VERSION 5.7 ;
  NOWIREEXTENSIONATPIN ON ;
  DIVIDERCHAR "/" ;
  BUSBITCHARS "[]" ;
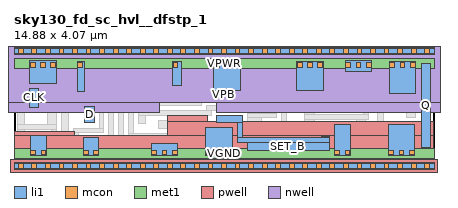
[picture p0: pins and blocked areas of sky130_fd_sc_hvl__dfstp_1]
MACRO sky130_fd_sc_hvl__dfstp_1
  CLASS BLOCK ;
  FOREIGN sky130_fd_sc_hvl__dfstp_1 ;
  ORIGIN 0.000 0.000 ;
  SIZE 14.880 BY 4.070 ;
  PIN CLK
    ANTENNAGATEAREA 0.585000 ;
    PORT
      LAYER li1 ;
        RECT 0.545 2.075 0.875 2.745 ;
    END
  END CLK
  PIN D
    ANTENNAGATEAREA 0.420000 ;
    PORT
      LAYER li1 ;
        RECT 2.505 1.525 2.835 2.095 ;
    END
  END D
  PIN SET_B
    ANTENNAGATEAREA 0.840000 ;
    PORT
      LAYER li1 ;
        RECT 7.165 1.555 8.100 1.795 ;
        RECT 7.930 1.010 8.100 1.555 ;
        RECT 10.885 1.010 11.160 1.040 ;
        RECT 7.930 0.840 11.160 1.010 ;
        RECT 8.285 0.555 11.160 0.840 ;
    END
  END SET_B
  PIN VGND
    USE GROUND ;
    PORT
      LAYER li1 ;
        RECT 0.570 0.365 1.160 1.115 ;
        RECT 2.470 0.365 3.005 0.995 ;
        RECT 4.855 0.365 5.805 0.785 ;
        RECT 6.800 0.365 7.750 1.375 ;
        RECT 11.340 0.365 11.930 1.475 ;
        RECT 13.255 0.365 14.205 1.475 ;
      LAYER mcon ;
        RECT 0.600 0.395 0.770 0.565 ;
        RECT 0.960 0.395 1.130 0.565 ;
        RECT 2.470 0.395 2.640 0.565 ;
        RECT 2.830 0.395 3.000 0.565 ;
        RECT 4.885 0.395 5.055 0.565 ;
        RECT 5.245 0.395 5.415 0.565 ;
        RECT 5.605 0.395 5.775 0.565 ;
        RECT 6.830 0.395 7.000 0.565 ;
        RECT 7.190 0.395 7.360 0.565 ;
        RECT 7.550 0.395 7.720 0.565 ;
        RECT 11.370 0.395 11.540 0.565 ;
        RECT 11.730 0.395 11.900 0.565 ;
        RECT 13.285 0.395 13.455 0.565 ;
        RECT 13.645 0.395 13.815 0.565 ;
        RECT 14.005 0.395 14.175 0.565 ;
      LAYER met1 ;
        RECT 0.000 0.255 14.880 0.625 ;
    END
  END VGND
  PIN VNB
    ANTENNADIFFAREA 2.529600 ;
    PORT
      LAYER pwell ;
        RECT 5.445 1.565 6.870 1.805 ;
        RECT 0.020 1.085 2.130 1.205 ;
        RECT 5.445 1.085 14.860 1.565 ;
        RECT 0.020 0.215 14.860 1.085 ;
        RECT -0.130 -0.215 15.010 0.215 ;
      LAYER li1 ;
        RECT 0.000 -0.085 14.880 0.085 ;
      LAYER mcon ;
        RECT 0.155 -0.085 0.325 0.085 ;
        RECT 0.635 -0.085 0.805 0.085 ;
        RECT 1.115 -0.085 1.285 0.085 ;
        RECT 1.595 -0.085 1.765 0.085 ;
        RECT 2.075 -0.085 2.245 0.085 ;
        RECT 2.555 -0.085 2.725 0.085 ;
        RECT 3.035 -0.085 3.205 0.085 ;
        RECT 3.515 -0.085 3.685 0.085 ;
        RECT 3.995 -0.085 4.165 0.085 ;
        RECT 4.475 -0.085 4.645 0.085 ;
        RECT 4.955 -0.085 5.125 0.085 ;
        RECT 5.435 -0.085 5.605 0.085 ;
        RECT 5.915 -0.085 6.085 0.085 ;
        RECT 6.395 -0.085 6.565 0.085 ;
        RECT 6.875 -0.085 7.045 0.085 ;
        RECT 7.355 -0.085 7.525 0.085 ;
        RECT 7.835 -0.085 8.005 0.085 ;
        RECT 8.315 -0.085 8.485 0.085 ;
        RECT 8.795 -0.085 8.965 0.085 ;
        RECT 9.275 -0.085 9.445 0.085 ;
        RECT 9.755 -0.085 9.925 0.085 ;
        RECT 10.235 -0.085 10.405 0.085 ;
        RECT 10.715 -0.085 10.885 0.085 ;
        RECT 11.195 -0.085 11.365 0.085 ;
        RECT 11.675 -0.085 11.845 0.085 ;
        RECT 12.155 -0.085 12.325 0.085 ;
        RECT 12.635 -0.085 12.805 0.085 ;
        RECT 13.115 -0.085 13.285 0.085 ;
        RECT 13.595 -0.085 13.765 0.085 ;
        RECT 14.075 -0.085 14.245 0.085 ;
        RECT 14.555 -0.085 14.725 0.085 ;
      LAYER met1 ;
        RECT 0.000 -0.115 14.880 0.115 ;
    END
  END VNB
  PIN VPB
    ANTENNADIFFAREA 2.529600 ;
    PORT
      LAYER nwell ;
        RECT -0.330 2.245 15.210 4.485 ;
        RECT -0.330 1.885 5.145 2.245 ;
        RECT 7.170 1.885 15.210 2.245 ;
      LAYER li1 ;
        RECT 0.000 3.985 14.880 4.155 ;
      LAYER mcon ;
        RECT 0.155 3.985 0.325 4.155 ;
        RECT 0.635 3.985 0.805 4.155 ;
        RECT 1.115 3.985 1.285 4.155 ;
        RECT 1.595 3.985 1.765 4.155 ;
        RECT 2.075 3.985 2.245 4.155 ;
        RECT 2.555 3.985 2.725 4.155 ;
        RECT 3.035 3.985 3.205 4.155 ;
        RECT 3.515 3.985 3.685 4.155 ;
        RECT 3.995 3.985 4.165 4.155 ;
        RECT 4.475 3.985 4.645 4.155 ;
        RECT 4.955 3.985 5.125 4.155 ;
        RECT 5.435 3.985 5.605 4.155 ;
        RECT 5.915 3.985 6.085 4.155 ;
        RECT 6.395 3.985 6.565 4.155 ;
        RECT 6.875 3.985 7.045 4.155 ;
        RECT 7.355 3.985 7.525 4.155 ;
        RECT 7.835 3.985 8.005 4.155 ;
        RECT 8.315 3.985 8.485 4.155 ;
        RECT 8.795 3.985 8.965 4.155 ;
        RECT 9.275 3.985 9.445 4.155 ;
        RECT 9.755 3.985 9.925 4.155 ;
        RECT 10.235 3.985 10.405 4.155 ;
        RECT 10.715 3.985 10.885 4.155 ;
        RECT 11.195 3.985 11.365 4.155 ;
        RECT 11.675 3.985 11.845 4.155 ;
        RECT 12.155 3.985 12.325 4.155 ;
        RECT 12.635 3.985 12.805 4.155 ;
        RECT 13.115 3.985 13.285 4.155 ;
        RECT 13.595 3.985 13.765 4.155 ;
        RECT 14.075 3.985 14.245 4.155 ;
        RECT 14.555 3.985 14.725 4.155 ;
      LAYER met1 ;
        RECT 0.000 3.955 14.880 4.185 ;
    END
  END VPB
  PIN VPWR
    USE POWER ;
    PORT
      LAYER li1 ;
        RECT 0.545 2.925 1.495 3.755 ;
        RECT 2.235 2.625 2.485 3.705 ;
        RECT 5.605 2.855 5.935 3.705 ;
        RECT 7.075 2.675 8.025 3.705 ;
        RECT 10.010 2.665 10.960 3.705 ;
        RECT 11.730 3.355 12.680 3.735 ;
        RECT 13.295 2.575 14.240 3.705 ;
      LAYER mcon ;
        RECT 0.575 3.505 0.745 3.675 ;
        RECT 0.935 3.505 1.105 3.675 ;
        RECT 1.295 3.505 1.465 3.675 ;
        RECT 2.265 3.505 2.435 3.675 ;
        RECT 5.635 3.505 5.805 3.675 ;
        RECT 7.105 3.505 7.275 3.675 ;
        RECT 7.465 3.505 7.635 3.675 ;
        RECT 7.825 3.505 7.995 3.675 ;
        RECT 10.040 3.505 10.210 3.675 ;
        RECT 10.400 3.505 10.570 3.675 ;
        RECT 10.760 3.505 10.930 3.675 ;
        RECT 11.760 3.505 11.930 3.675 ;
        RECT 12.120 3.505 12.290 3.675 ;
        RECT 12.480 3.505 12.650 3.675 ;
        RECT 13.320 3.505 13.490 3.675 ;
        RECT 13.680 3.505 13.850 3.675 ;
        RECT 14.040 3.505 14.210 3.675 ;
      LAYER met1 ;
        RECT 0.000 3.445 14.880 3.815 ;
    END
  END VPWR
  PIN Q
    ANTENNADIFFAREA 0.478750 ;
    PORT
      LAYER li1 ;
        RECT 14.420 0.645 14.770 3.615 ;
    END
  END Q
  OBS
      LAYER li1 ;
        RECT 0.115 1.465 0.365 3.735 ;
        RECT 1.675 2.945 2.005 3.735 ;
        RECT 1.690 2.445 2.005 2.945 ;
        RECT 2.665 2.445 2.835 3.755 ;
        RECT 1.690 2.275 2.835 2.445 ;
        RECT 3.015 3.285 5.005 3.615 ;
        RECT 8.695 3.595 9.825 3.805 ;
        RECT 1.180 1.465 1.510 1.895 ;
        RECT 0.115 1.295 1.510 1.465 ;
        RECT 0.115 0.615 0.380 1.295 ;
        RECT 1.340 0.435 1.510 1.295 ;
        RECT 1.690 0.615 1.940 2.275 ;
        RECT 3.015 1.345 3.185 3.285 ;
        RECT 2.120 1.175 3.185 1.345 ;
        RECT 2.120 0.435 2.290 1.175 ;
        RECT 3.365 0.995 3.535 3.105 ;
        RECT 3.715 1.085 3.885 3.285 ;
        RECT 4.065 2.605 4.395 3.105 ;
        RECT 4.065 1.135 4.235 2.605 ;
        RECT 4.835 2.325 5.005 3.285 ;
        RECT 5.185 2.675 5.425 3.555 ;
        RECT 6.565 2.845 6.895 3.105 ;
        RECT 6.115 2.675 6.895 2.845 ;
        RECT 8.695 2.845 8.865 3.595 ;
        RECT 9.045 3.025 9.660 3.415 ;
        RECT 11.300 3.255 11.550 3.755 ;
        RECT 8.695 2.675 9.310 2.845 ;
        RECT 5.185 2.505 6.285 2.675 ;
        RECT 6.465 2.325 8.960 2.495 ;
        RECT 4.415 1.975 4.655 2.165 ;
        RECT 4.835 2.155 6.635 2.325 ;
        RECT 6.815 1.975 8.450 2.145 ;
        RECT 8.630 2.085 8.960 2.325 ;
        RECT 4.415 1.805 6.985 1.975 ;
        RECT 8.280 1.875 8.450 1.975 ;
        RECT 9.140 1.875 9.310 2.675 ;
        RECT 4.415 1.495 4.655 1.805 ;
        RECT 8.280 1.705 9.310 1.875 ;
        RECT 9.490 2.485 9.660 3.025 ;
        RECT 11.380 3.175 11.550 3.255 ;
        RECT 11.380 3.005 12.560 3.175 ;
        RECT 11.410 2.675 11.740 2.825 ;
        RECT 11.410 2.485 12.210 2.675 ;
        RECT 9.490 2.315 12.210 2.485 ;
        RECT 5.135 1.315 5.865 1.625 ;
        RECT 8.280 1.545 8.785 1.705 ;
        RECT 9.490 1.475 9.660 2.315 ;
        RECT 10.305 1.825 10.635 2.135 ;
        RECT 11.880 2.005 12.210 2.315 ;
        RECT 12.390 1.825 12.560 3.005 ;
        RECT 10.305 1.655 12.560 1.825 ;
        RECT 12.865 2.395 13.115 3.365 ;
        RECT 12.865 2.225 14.240 2.395 ;
        RECT 10.305 1.545 10.635 1.655 ;
        RECT 9.025 1.190 9.660 1.475 ;
        RECT 3.185 0.495 3.535 0.995 ;
        RECT 4.065 0.965 6.315 1.135 ;
        RECT 12.120 0.975 12.450 1.655 ;
        RECT 12.865 1.475 13.075 2.225 ;
        RECT 13.910 1.725 14.240 2.225 ;
        RECT 12.745 0.975 13.075 1.475 ;
        RECT 4.065 0.495 4.315 0.965 ;
        RECT 1.340 0.265 2.290 0.435 ;
        RECT 5.985 0.265 6.315 0.965 ;
  END
END sky130_fd_sc_hvl__dfstp_1
END LIBRARY

